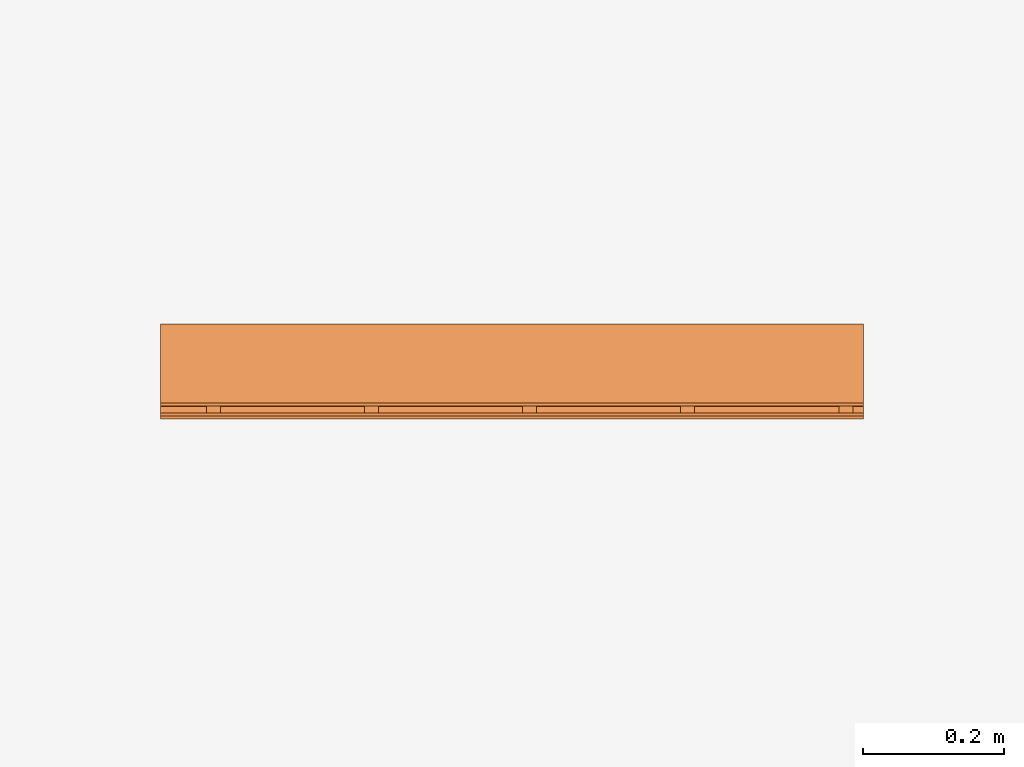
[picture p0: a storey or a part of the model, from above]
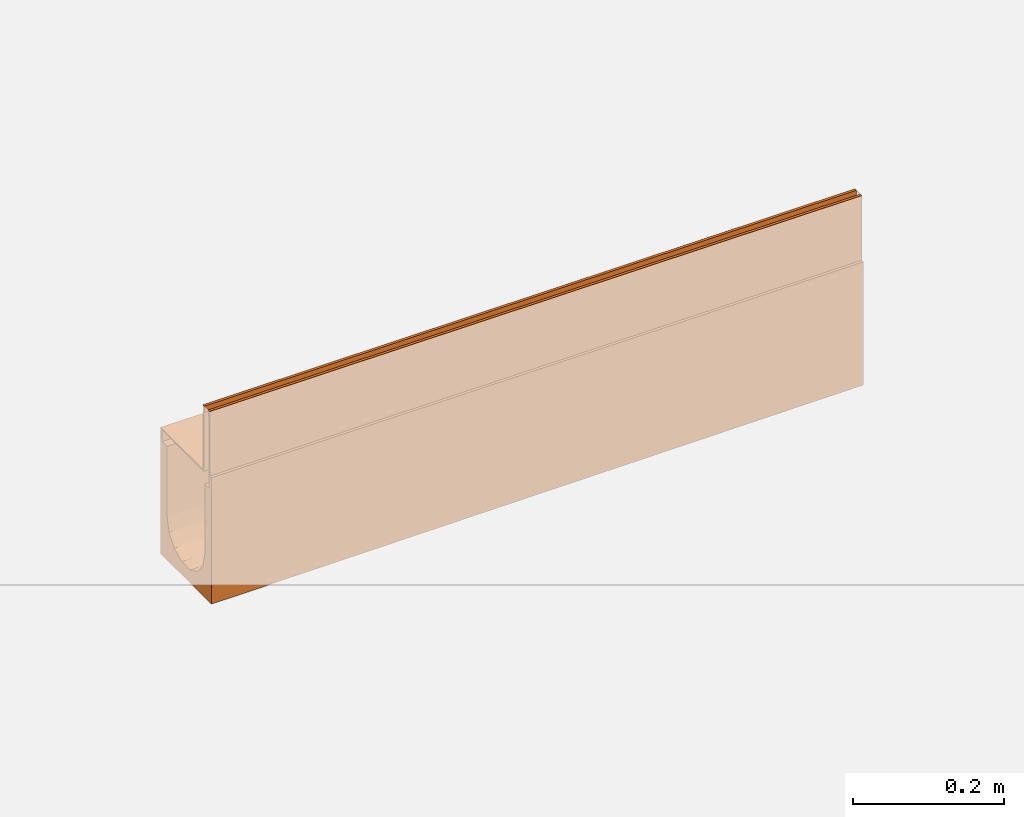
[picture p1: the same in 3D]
Properties of the parts of a building model (IFC2X3)

# File
Description: ViewDefinition [CoordinationView]
File name: 23011 - No 11 Sloping Channel - 1000mm LG - Invert Depth 180-185mm.ifc
Time: 2013-10-31T17:26:25
Written by: Autodesk Revit 2013
Made in: 20120221_2030(x64)

# IfcProject, Project Number
LongName: Project Name; Phase: Project Status

# IfcSite, Default
RefLatitude: 42, 21, 30, 344238; RefLongitude: -71, -3, -35, -194702; RefElevation: 0 mm

# IfcBuilding
Pset_BuildingCommon - NumberOfStoreys: 1
Other - Client Name: Owner; Project Name: Project Name; Project Issue Date: Issue Date; Project Number: Project Number; Project Status: Project Status; Project Address: ## Street City, State Zip

# IfcBuildingStorey, Level 1
LongName: Level 1; Elevation: 0 mm
Constraints - Elevation Base: 0; Elevation: 0 mm
Graphics - Color: 0; Symbol at End 1 Default: no; Line Pattern: Center; Symbol: M_Level Head - Circle: M_Level Head - Circle; Line Weight: 1; Symbol at End 2 Default: yes
Identity Data - Building Story: yes; Structural: no; Name: Level 1
Dimensions - Computation Height: 0 mm

# IfcBuildingElementProxy: 23011 - No 11 Sloping Channel - 1000mm LG - Invert Depth 180/185mm, Civil-Drainage-Channel-ACO-MultiDrain-M100D-Brickslot-Channel-System:23011 - No 11 Sloping Channel - 1000mm LG - Invert Depth 180/185mm:23011 - No 11 Sloping Channel - 1000mm LG - Invert Depth 180/185mm:196059
In: Level 1
Material: Steel, Galvanized, Vienite® Synthetic Resin Concrete
Phasing - Phase Created: New Construction
Construction - 23466_Load Class D400_Brickslot Grating_Galvanized Steel_500mm Long: no; 23404_Universal Endcap (Male End): no; 23462_Load Class C250_Brickslot Access Unit_Galvanised Steel_500mm Long: no; 23460_Load Class C250_Brickslot Grating_Galvanized Steel_1000mm Long: no; 23465_Load Class D400_Brickslot Grating_Galvanized Steel_1000mm Long: yes; 23461_Load Class C250_Brickslot Grating_Galvanized Steel_500mm Long: no; 23467_Load Class D400_Brickslot Access Unit_Galvanised Steel_500mm Long: no; 23404_Universal Endcap (Female End): no; 23410_Sump Unit: no; Shallow Depth Channel with seal: no; Shallow Depth Channel: no; Sloping Channel: yes; Constant Depth Junction Channel: no; Constant Depth Channel: no
Dimensions - Length: 1000 mm; Volume: 10426228 mm3; Custom_Void_length: 0 mm; Brickslot Void Length: 1000 mm; Brickslot Access Unit Void Bottom Depth: -6605 mm; Brickslot Void Depth: 0 mm; Brickslot Access Unit Void Depth: -6500 mm; EndCap Position: 1000 mm; FloorCut_Length: -1000 mm; FloorCut_Width: 135 mm; SlopingInvertDepth: 130 mm; Floor Cut Gap: 105 mm; EndCap_Height: 205 mm; SlopingOverallDepth: 200 mm; Depth: 150 mm; ShallowOverallDepth: 75 mm; FloorCut_Depth: 205 mm; Length Drain: -1000 mm; InvDepth: 80 mm; GratingLength: -1000 mm; SlopingEndOverallDepth: 205 mm; ShallowInvDepth: 55 mm; SlopingEndInvertDepth: 135 mm; Brickslot Access Unit Floor Cut Length: 500 mm; Access_Custom_Void_Length: 0 mm
Constraints - Moves With Nearby Elements: no; Level: Level: Level 1
Pset_BuildingElementProxyCommon - Reference: 23011 - No 11 Sloping Channel - 1000mm LG - Invert Depth 180/185mm
Identity Data - Assembly Description: Rain Water Drainage; Address: ACO Business Park, Hitchin Road, Shefford, Bedfordshire, United Kingdom SG17 5TE; Fax: +44 (0)1462 815895; Type Comments: ACO MultiDrain M100D No 11 Sloping Channel 1000mm Long; Installation guidelines: http://www.aco.co.uk/download.php?id=173; Product Page URL: http://www.aco.co.uk/product_detail.php?id=58; Product Code: 23011; OmniClass Number: 23.70.50.24; Telephone: +44 (0)1462 816666; Watermark 2: This file is water marked and users are prohibited to reproduce, adapt, distribute this information; Model: ACO MultiDrain MD Brickslot- M100D; Watermarked With: BIM Manager Premium Suite; Price: POA - contact ACO; Maintenance guidelines: http://www.aco.co.uk/download.php?id=173; Cost: 0; OmniClass Title: Rainwater Removal; URL: www.aco.co.uk; e-mail Technical: technical@aco.co.uk; Model Description: Channel drainage system; Product brochure: http://www.aco.co.uk/download.php?id=173; Assembly Code: D2040; Watermark 1: This file is the property of ACO Technologies PLC; Manufacturer: ACO Technologies plc - ACO Water Management Division; e-mail Sales: customersupport@aco.co.uk
Data - Channel C.S.A: N/A; Product Standard: BS EN 1433:2002, CE marked; Concrete Surround Volume - Load Class B 125 - C 250 - Concrete Pavement: N/A; Product Weight: 16.5 Kg; Product Dimensions: 1000mm x 135mm x 200mm/205mm (LxWxH); Load Class: A 15 - D 400; Pre-formed Outlet Ø: N/A; Invert Depth: 180mm/185mm; Concrete Surround Volume - Load Class A 15 - Concrete Pavement: N/A; Hydraulic Performance: http://www.aco.co.uk/download.php?id=173; Concrete Surround Volume - Load Class D 400 - Concrete Pavement: N/A; Installation - Concrete Grade: Refer to brochure; ACO Hydraulic Design Software: http://www.acodesign.co.uk
General - SerialNumber: 0; TagNumber: 0
Other - Watermarked By: www.aco.co.uk; Created By: www.aco.co.uk; Revision: 1
Model Properties - Brickslot Grating Product code 23460: Load Class C250 - Brickslot Galvanised Steel - 1000mm long x 105mm high - 10mm Slot - Intake area - 10000mm²/m - 6.6 Kg; Brickslot Grating Product code 23466: Load Class D400 - Brickslot Galvanised Steel - 500mm long x 105mm high - 10mm Slot - Intake area - 10000mm²/m - 3.3 Kg; Brickslot Grating Product code 23461: Load Class C250 - Brickslot Galvanised Steel - 500mm long x 105mm high - 10mm Slot - Intake area - 10000mm²/m -3.3 Kg; End Cap Product code 23404: No 306 Universal End Cap - 135mm wide x 300mm long - Spigot Ø110mm x 50mm long - Silver - Polypropylene - 0.16kg; Brickslot Access Unit Product code 23467: Load Class D400 - Brickslot Access Unit Galvanised Steel - 500mm long x 105mm high - 10mm Slot - Intake area - 10000mm²/m - 6.4 Kg; Brickslot Access Unit Product code 23462: Load Class C250 - Brickslot Access Unit Galvanised Steel - 500mm long x 105mm high - 10mm Slot - Intake area - 10000mm²/m - 6.4 Kg; Brickslot Grating Product code 23465: Load Class D400 - Brickslot Galvanised Steel - 1000mm long x 105mm high - 10mm Slot - Intake area - 10000mm²/m - 6.6 Kg
Materials and Finishes - Channel Colour: Brown; Edge Rail Colour: Silver; Edge Rail Material: Steel; Channel Material: Vienite® Synthetic Resin Concrete; Edge Rail Finish: Pre-galvanised
Green Building Properties - Edge Rail Recyclable: Fully recyclable; Edge Rail Recycled Material Content: Between 40% - 90%; Channel Recyclable: Fully recyclable; Channel Recycled Material Content: 20% minimum

# IfcOpeningElement: Recess (2)
In: Level 1
Dimensions - Perimeter: 20000 mm; Area: 25000000 mm2; Thickness: 1000 mm; Volume: 24970435000 mm3
Structural - Enable Analytical Model: no; Structural: no
Phasing - Phase Created: New Construction
Constraints - Height Offset From Level: 0 mm; Level: Level: Level 1; Related to Mass: no; Room Bounding: yes
Materials and Finishes - Structural Material: Earth
Analytical Properties - Thermal Resistance (R): 1.19474; Heat Transfer Coefficient (U): 0.837; Absorptance: 0.1; Roughness: 1; Thermal mass: 1359800
Construction - Default Thickness: 1000 mm; Function: 0
Graphics - Coarse Scale Fill Color: 0

# IfcSlab: Floor:Generic Floor - 1000mm, Floor:Generic Floor - 1000mm:193825
In: Level 1
PredefinedType: FLOOR; Material: Earth 1000 mm
Dimensions - Perimeter: 20000 mm; Area: 25000000 mm2; Thickness: 1000 mm; Volume: 24970435000 mm3
Structural - Enable Analytical Model: no; Structural: no
Phasing - Phase Created: New Construction
Constraints - Height Offset From Level: 0 mm; Level: Level: Level 1; Related to Mass: no; Room Bounding: yes
Pset_SlabCommon - Reference: Generic Floor - 1000mm; IsExternal: no; LoadBearing: yes
Materials and Finishes - Structural Material: Earth
Analytical Properties - Thermal Resistance (R): 1.19474; Heat Transfer Coefficient (U): 0.837; Absorptance: 0.1; Roughness: 1; Thermal mass: 1359800
Construction - Default Thickness: 1000 mm; Function: 0
Graphics - Coarse Scale Fill Color: 0
